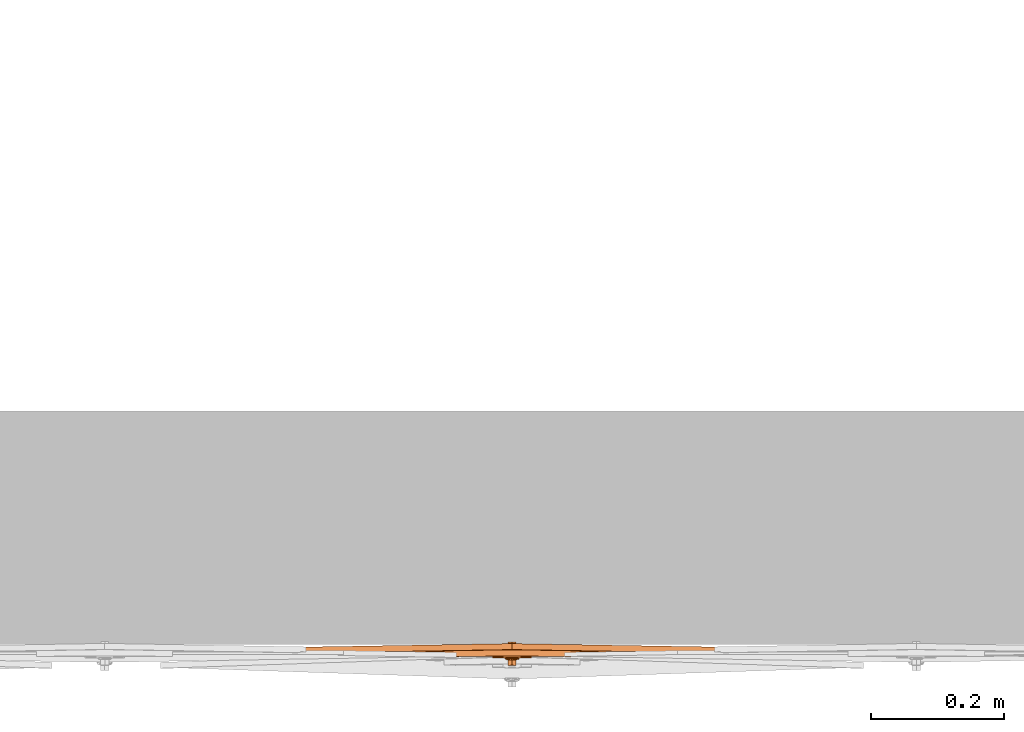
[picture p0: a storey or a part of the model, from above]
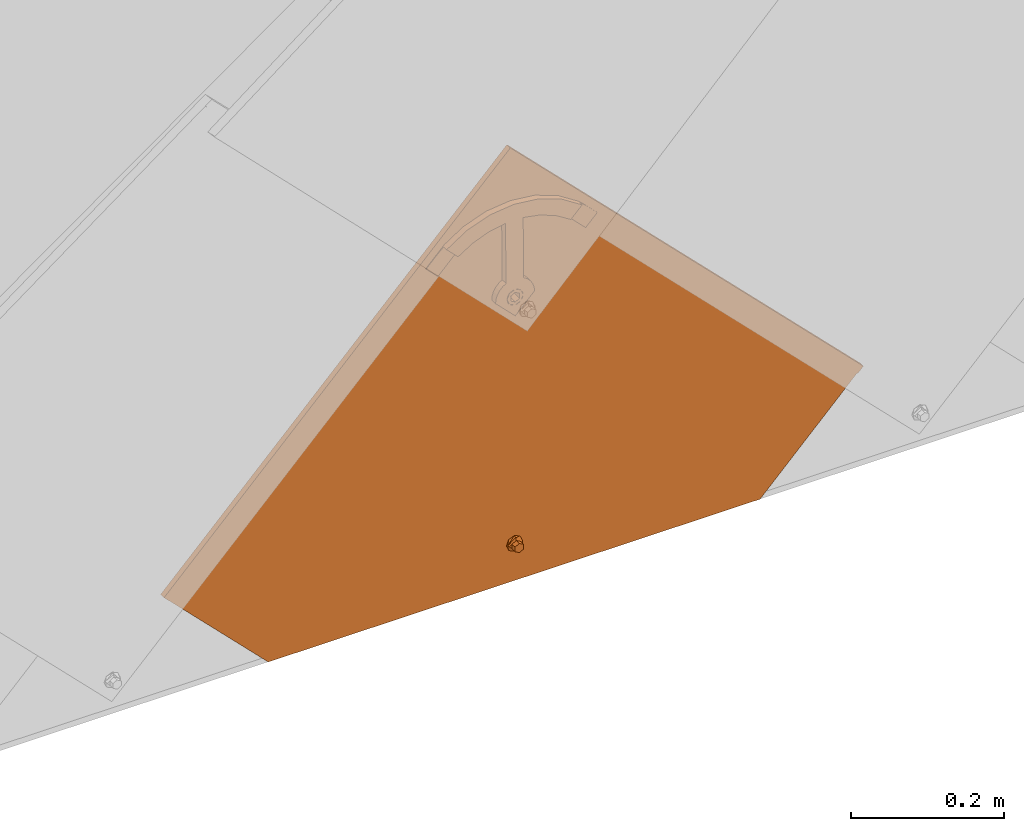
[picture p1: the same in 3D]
Properties of the parts of a building model (IFC2X3)

# File
Description: ViewDefinition [CoordinationView_V2.0]
File name: 0001
Time: 2023-04-02T02:29:55
Written by: The EXPRESS Data Manager Version 5.02.0100.07 : 28 Aug 2013
Made in: 20190327_2315(x64) - Exporter 20.0.0.377 - Alternate UI 20.0.0.377
Comment: STEP Physical File produced by: The EXPRESS Data Manager Version 5.02.0100.07 : 28 Aug 2013 * Module: EDMstepFileFactory/EDMstandAlone * Creation date: Sun Apr 02 02:29:55 2023 * Host: E7270 * Database: C:\Users\GOODLU~1\AppData\Local\Temp\f6eb3f9f-7fa0-42ba-b934-946579097e53\dbb1e1d8-6f93-475a-80dd-ea82b20c156a\ifc * Database version: 5507 * Database creation date: Sun Apr 02 02:29:47 2023 * Schema: IFC2X3 * Model: DataRepository.ifc * Model creation date: Sun Apr 02 02:29:48 2023 * Header model: DataRepository.ifc_HeaderModel * Header model creation date: Sun Apr 02 02:29:48 2023 * EDMuser: sdai-user * EDMgroup: sdai-group * License ID and type: 5605 : Permanent license. Expiry date: * EDMstepFileFactory options: 020000

# IfcProject, 0001
LongName: Project Name; Phase: Project Status

# IfcSite, Default
RefLatitude: 42, 21, 30, 344238; RefLongitude: -71, -3, -35, -194702; RefElevation: 0 mm

# IfcBuilding
Pset_BuildingCommon - NumberOfStoreys: 2
Pset_ProductRequirements - Category: Project Information

# IfcBuildingStorey: Level:8mm Head (2)
Pset_ProductRequirements - Category: Levels
Name | LongName = Pset_AirSideSystemInformation, Name = Pset_ProductRequirements, Name | Elevation (mm)
Level 1 | Level 1 | 0
Level 2 | Level 2 | 2687.5

# IfcBuildingElementProxy: Corner Bottom Big Left - Black, Roofing_Panels_SunStyle_Tile_Corner-Bottom-Big-Left:Corner Bottom Big Left - Black:395826
In: Level 1
Type - Classification: B3010150 Roofing - Shingle & Tile (Uniformat); Material: Rubber - Sunstyle - Black, Glass - Sunstyle - Tainted Black
Type - Pset_BuildingElementProxyCommon - Reference: Corner Bottom Big Left - Black
Type - Pset_ManufacturerTypeInformation - Manufacturer: SunStyle
Type - Pset_ProductRequirements - Category: Generic Models
Type - Pset_QuantityTakeOff - Reference: Corner Bottom Big Left - Black
Pset_BuildingElementProxyCommon - sets with these values: 2

# IfcBuildingElementProxy: Corner Bottom Big Right - Black (12)
In: Level 1
Type - Classification: B3010150 Roofing - Shingle & Tile (Uniformat); Material: Rubber - Sunstyle - Black, Glass - Sunstyle - Tainted Black
Type - Pset_BuildingElementProxyCommon - Reference: Corner Bottom Big Right - Black
Type - Pset_ManufacturerTypeInformation - Manufacturer: SunStyle
Type - Pset_ProductRequirements - Category: Generic Models
Type - Pset_QuantityTakeOff - Reference: Corner Bottom Big Right - Black
Pset_BuildingElementProxyCommon - sets with these values: 2
Name (Roofing_Panels_SunStyle_Tile_Corner-Bottom-Big-Right:Corner Bottom Big Right - Black:...)
369701
377953
378203
386429
395871
516759
525238
525277
525309
525338
525370
525403

# IfcBuildingElementProxy: Corner Bottom Big Right - Terracotta, Roofing_Panels_SunStyle_Tile_Corner-Bottom-Big-Right:Corner Bottom Big Right - Terracotta:399702
In: Level 1
Type - Classification: B3010150 Roofing - Shingle & Tile (Uniformat); Material: Rubber - Sunstyle - Black, Glass - Sunstyle - Tainted Terracotta
Type - Pset_BuildingElementProxyCommon - Reference: Corner Bottom Big Right - Terracotta
Type - Pset_ManufacturerTypeInformation - Manufacturer: SunStyle
Type - Pset_ProductRequirements - Category: Generic Models
Type - Pset_QuantityTakeOff - Reference: Corner Bottom Big Right - Terracotta
Pset_BuildingElementProxyCommon - sets with these values: 2

# IfcBuildingElementProxy: Corner Bottom Small Left - Black (4)
In: Level 1
Type - Classification: B3010150 Roofing - Shingle & Tile (Uniformat); Material: Rubber - Sunstyle - Black, Glass - Sunstyle - Tainted Black
Type - Pset_BuildingElementProxyCommon - Reference: Corner Bottom Small Left - Black
Type - Pset_ManufacturerTypeInformation - Manufacturer: SunStyle
Type - Pset_ProductRequirements - Category: Generic Models
Type - Pset_QuantityTakeOff - Reference: Corner Bottom Small Left - Black
Pset_BuildingElementProxyCommon - sets with these values: 2
Name (Roofing_Panels_SunStyle_Tile_Corner-Bottom-Small-Left:Corner Bottom Small Left - Black:...)
369142
380725
385739
395835

# IfcBuildingElementProxy: Corner Bottom Small Left - Terracotta, Roofing_Panels_SunStyle_Tile_Corner-Bottom-Small-Left:Corner Bottom Small Left - Terracotta:401538
In: Level 1
Type - Classification: B3010150 Roofing - Shingle & Tile (Uniformat); Material: Rubber - Sunstyle - Black, Glass - Sunstyle - Tainted Terracotta
Type - Pset_BuildingElementProxyCommon - Reference: Corner Bottom Small Left - Terracotta
Type - Pset_ManufacturerTypeInformation - Manufacturer: SunStyle
Type - Pset_ProductRequirements - Category: Generic Models
Type - Pset_QuantityTakeOff - Reference: Corner Bottom Small Left - Terracotta
Pset_BuildingElementProxyCommon - sets with these values: 2

# IfcBuildingElementProxy: Corner Bottom Small Right - Black, Roofing_Panels_SunStyle_Tile_Corner-Bottom-Small-Right:Corner Bottom Small Right - Black:395880
In: Level 1
Type - Classification: B3010150 Roofing - Shingle & Tile (Uniformat); Material: Rubber - Sunstyle - Black, Glass - Sunstyle - Tainted Black
Type - Pset_BuildingElementProxyCommon - Reference: Corner Bottom Small Right - Black
Type - Pset_ManufacturerTypeInformation - Manufacturer: SunStyle
Type - Pset_ProductRequirements - Category: Generic Models
Type - Pset_QuantityTakeOff - Reference: Corner Bottom Small Right - Black
Pset_BuildingElementProxyCommon - sets with these values: 2

# IfcBuildingElementProxy: Corner Top Big Left - Black (3)
In: Level 1
Type - Classification: B3010150 Roofing - Shingle & Tile (Uniformat); Material: Rubber - Sunstyle - Black, Glass - Sunstyle - Tainted Black
Type - Pset_BuildingElementProxyCommon - Reference: Corner Top Big Left - Black
Type - Pset_ManufacturerTypeInformation - Manufacturer: SunStyle
Type - Pset_ProductRequirements - Category: Generic Models
Type - Pset_QuantityTakeOff - Reference: Corner Top Big Left - Black
Pset_BuildingElementProxyCommon - sets with these values: 2
Name (Roofing_Panels_SunStyle_Tile_Corner-Top-Big-Left:Corner Top Big Left - Black:...)
366997
386258
395853

# IfcBuildingElementProxy: Corner Top Big Left - Terracotta, Roofing_Panels_SunStyle_Tile_Corner-Top-Big-Left:Corner Top Big Left - Terracotta:400910
In: Level 1
Type - Classification: B3010150 Roofing - Shingle & Tile (Uniformat); Material: Rubber - Sunstyle - Black, Glass - Sunstyle - Tainted Terracotta
Type - Pset_BuildingElementProxyCommon - Reference: Corner Top Big Left - Terracotta
Type - Pset_ManufacturerTypeInformation - Manufacturer: SunStyle
Type - Pset_ProductRequirements - Category: Generic Models
Type - Pset_QuantityTakeOff - Reference: Corner Top Big Left - Terracotta
Pset_BuildingElementProxyCommon - sets with these values: 2

# IfcBuildingElementProxy: Corner Top Big Right - Black, Roofing_Panels_SunStyle_Tile_Corner-Top-Big-Right:Corner Top Big Right - Black:395898
In: Level 1
Type - Classification: B3010150 Roofing - Shingle & Tile (Uniformat); Material: Rubber - Sunstyle - Black, Glass - Sunstyle - Tainted Black
Type - Pset_BuildingElementProxyCommon - Reference: Corner Top Big Right - Black
Type - Pset_ManufacturerTypeInformation - Manufacturer: SunStyle
Type - Pset_ProductRequirements - Category: Generic Models
Type - Pset_QuantityTakeOff - Reference: Corner Top Big Right - Black
Pset_BuildingElementProxyCommon - sets with these values: 2

# IfcBuildingElementProxy: Corner Top Small Left - Black, Roofing_Panels_SunStyle_Tile_Corner-Top-Small-Left:Corner Top Small Left - Black:395862
In: Level 1
Type - Classification: B3010150 Roofing - Shingle & Tile (Uniformat); Material: Rubber - Sunstyle - Black, Glass - Sunstyle - Tainted Black
Type - Pset_BuildingElementProxyCommon - Reference: Corner Top Small Left - Black
Type - Pset_ManufacturerTypeInformation - Manufacturer: SunStyle
Type - Pset_ProductRequirements - Category: Generic Models
Type - Pset_QuantityTakeOff - Reference: Corner Top Small Left - Black
Pset_BuildingElementProxyCommon - sets with these values: 2

# IfcBuildingElementProxy: Corner Top Small Right - Black (3)
In: Level 1
Type - Classification: B3010150 Roofing - Shingle & Tile (Uniformat); Material: Rubber - Sunstyle - Black, Glass - Sunstyle - Tainted Black
Type - Pset_BuildingElementProxyCommon - Reference: Corner Top Small Right - Black
Type - Pset_ManufacturerTypeInformation - Manufacturer: SunStyle
Type - Pset_ProductRequirements - Category: Generic Models
Type - Pset_QuantityTakeOff - Reference: Corner Top Small Right - Black
Pset_BuildingElementProxyCommon - sets with these values: 2
Name (Roofing_Panels_SunStyle_Tile_Corner-Top-Small-Right:Corner Top Small Right - Black:...)
379696
386932
395907

# IfcBuildingElementProxy: Corner Top Small Right - Terracotta, Roofing_Panels_SunStyle_Tile_Corner-Top-Small-Right:Corner Top Small Right - Terracotta:400462
In: Level 1
Type - Classification: B3010150 Roofing - Shingle & Tile (Uniformat); Material: Rubber - Sunstyle - Black, Glass - Sunstyle - Tainted Terracotta
Type - Pset_BuildingElementProxyCommon - Reference: Corner Top Small Right - Terracotta
Type - Pset_ManufacturerTypeInformation - Manufacturer: SunStyle
Type - Pset_ProductRequirements - Category: Generic Models
Type - Pset_QuantityTakeOff - Reference: Corner Top Small Right - Terracotta
Pset_BuildingElementProxyCommon - sets with these values: 2

# IfcBuildingElementProxy: Non PV Shingle - Black (9)
In: Level 1
Type - Classification: B3010150 Roofing - Shingle & Tile (Uniformat); Material: Rubber - Sunstyle - Black, Glass - Sunstyle - Tainted Black
Type - Pset_BuildingElementProxyCommon - Reference: Non PV Shingle - Black
Type - Pset_ManufacturerTypeInformation - Manufacturer: SunStyle
Type - Pset_ProductRequirements - Category: Generic Models
Type - Pset_QuantityTakeOff - Reference: Non PV Shingle - Black
Pset_BuildingElementProxyCommon - sets with these values: 2
Name (Roofing_Panels_SunStyle_Tile_Non-PV-Shingle:Non PV Shingle - Black:...)
384084
384306
384333
384420
384541
384610
384709
384800
395796

# IfcBuildingElementProxy: Non PV Shingle - Silver, Roofing_Panels_SunStyle_Tile_Non-PV-Shingle:Non PV Shingle - Silver:403169
In: Level 2
Type - Classification: B3010150 Roofing - Shingle & Tile (Uniformat); Material: Rubber - Sunstyle - Black, Glass - Sunstyle - Tainted Silver
Type - Pset_BuildingElementProxyCommon - Reference: Non PV Shingle - Silver
Type - Pset_ManufacturerTypeInformation - Manufacturer: SunStyle
Type - Pset_ProductRequirements - Category: Generic Models
Type - Pset_QuantityTakeOff - Reference: Non PV Shingle - Silver
Pset_BuildingElementProxyCommon - sets with these values: 2

# IfcBuildingElementProxy: Non PV Shingle - Terracotta (4)
In: Level 1
Type - Classification: B3010150 Roofing - Shingle & Tile (Uniformat); Material: Rubber - Sunstyle - Black, Glass - Sunstyle - Tainted Terracotta
Type - Pset_BuildingElementProxyCommon - Reference: Non PV Shingle - Terracotta
Type - Pset_ManufacturerTypeInformation - Manufacturer: SunStyle
Type - Pset_ProductRequirements - Category: Generic Models
Type - Pset_QuantityTakeOff - Reference: Non PV Shingle - Terracotta
Pset_BuildingElementProxyCommon - sets with these values: 2
Name (Roofing_Panels_SunStyle_Tile_Non-PV-Shingle:Non PV Shingle - Terracotta:...)
398031
398120
498498
498499

# IfcBuildingElementProxy: Shingle Bottom - Black (11)
In: Level 1
Type - Classification: B3010150 Roofing - Shingle & Tile (Uniformat); Material: Rubber - Sunstyle - Black, Glass - Sunstyle - Tainted Black
Type - Pset_BuildingElementProxyCommon - Reference: Shingle Bottom - Black
Type - Pset_ManufacturerTypeInformation - Manufacturer: SunStyle
Type - Pset_ProductRequirements - Category: Generic Models
Type - Pset_QuantityTakeOff - Reference: Shingle Bottom - Black
Pset_BuildingElementProxyCommon - sets with these values: 2
Name (Roofing_Panels_SunStyle_Tile_Shingle-Bottom:Shingle Bottom - Black:...)
368326
385063
385148
395808
495417
495439
495456
495473
495487
495504
495520

# IfcBuildingElementProxy: Shingle Bottom - Terracotta (2)
In: Level 1
Type - Classification: B3010150 Roofing - Shingle & Tile (Uniformat); Material: Rubber - Sunstyle - Black, Glass - Sunstyle - Tainted Terracotta
Type - Pset_BuildingElementProxyCommon - Reference: Shingle Bottom - Terracotta
Type - Pset_ManufacturerTypeInformation - Manufacturer: SunStyle
Type - Pset_ProductRequirements - Category: Generic Models
Type - Pset_QuantityTakeOff - Reference: Shingle Bottom - Terracotta
Pset_BuildingElementProxyCommon - sets with these values: 2
Name (Roofing_Panels_SunStyle_Tile_Shingle-Bottom:Shingle Bottom - Terracotta:...)
398686
498471

# IfcBuildingElementProxy: Shingle Bottom Small - Black (19)
In: Level 1
Type - Classification: B3010150 Roofing - Shingle & Tile (Uniformat); Material: Rubber - Sunstyle - Black, Glass - Sunstyle - Tainted Black
Type - Pset_BuildingElementProxyCommon - Reference: Shingle Bottom Small - Black
Type - Pset_ManufacturerTypeInformation - Manufacturer: SunStyle
Type - Pset_ProductRequirements - Category: Generic Models
Type - Pset_QuantityTakeOff - Reference: Shingle Bottom Small - Black
Pset_BuildingElementProxyCommon - sets with these values: 2
Name (Roofing_Panels_SunStyle_Tile_Shingle-Bottom-Small:Shingle Bottom Small - Black:...)
367801
380429
387918
388031
395817
495637
495653
495669
495683
495697
495761
495787
524312
525246
525278
525310
525339
525371
525404

# IfcBuildingElementProxy: Shingle Bottom Small - Terracotta (2)
In: Level 1
Type - Classification: B3010150 Roofing - Shingle & Tile (Uniformat); Material: Rubber - Sunstyle - Black, Glass - Sunstyle - Tainted Terracotta
Type - Pset_BuildingElementProxyCommon - Reference: Shingle Bottom Small - Terracotta
Type - Pset_ManufacturerTypeInformation - Manufacturer: SunStyle
Type - Pset_ProductRequirements - Category: Generic Models
Type - Pset_QuantityTakeOff - Reference: Shingle Bottom Small - Terracotta
Pset_BuildingElementProxyCommon - sets with these values: 2
Name (Roofing_Panels_SunStyle_Tile_Shingle-Bottom-Small:Shingle Bottom Small - Terracotta:...)
401826
498501

# IfcBuildingElementProxy: Shingle Customisable - Black, Roofing_Panels_SunStyle_Tile_Shingle-Customisable:Shingle Customisable - Black:404367
In: Level 1
Type - Classification: B3010150 Roofing - Shingle & Tile (Uniformat); Material: Rubber - Sunstyle - Black, Glass - Sunstyle - Tainted Black
Type - Pset_BuildingElementProxyCommon - Reference: Shingle Customisable - Black
Type - Pset_ManufacturerTypeInformation - Manufacturer: SunStyle
Type - Pset_ProductRequirements - Category: Generic Models
Type - Pset_QuantityTakeOff - Reference: Shingle Customisable - Black
Pset_BuildingElementProxyCommon - sets with these values: 2

# IfcBuildingElementProxy: Shingle Left - Black (11)
In: Level 1
Type - Classification: B3010150 Roofing - Shingle & Tile (Uniformat); Material: Rubber - Sunstyle - Black, Glass - Sunstyle - Tainted Black
Type - Pset_BuildingElementProxyCommon - Reference: Shingle Left - Black
Type - Pset_ManufacturerTypeInformation - Manufacturer: SunStyle
Type - Pset_ProductRequirements - Category: Generic Models
Type - Pset_QuantityTakeOff - Reference: Shingle Left - Black
Pset_BuildingElementProxyCommon - sets with these values: 2
Name (Roofing_Panels_SunStyle_Tile_Shingle-Left:Shingle Left - Black:...)
363329
363472
363536
377368
377509
377580
377661
385898
385981
395844
522810

# IfcBuildingElementProxy: Shingle Left - Terracotta (2)
In: Level 1
Type - Classification: B3010150 Roofing - Shingle & Tile (Uniformat); Material: Rubber - Sunstyle - Black, Glass - Sunstyle - Tainted Terracotta
Type - Pset_BuildingElementProxyCommon - Reference: Shingle Left - Terracotta
Type - Pset_ManufacturerTypeInformation - Manufacturer: SunStyle
Type - Pset_ProductRequirements - Category: Generic Models
Type - Pset_QuantityTakeOff - Reference: Shingle Left - Terracotta
Pset_BuildingElementProxyCommon - sets with these values: 2
Name (Roofing_Panels_SunStyle_Tile_Shingle-Left:Shingle Left - Terracotta:...)
401137
401240

# IfcBuildingElementProxy: Shingle Right - Black (11)
In: Level 1
Type - Classification: B3010150 Roofing - Shingle & Tile (Uniformat); Material: Rubber - Sunstyle - Black, Glass - Sunstyle - Tainted Black
Type - Pset_BuildingElementProxyCommon - Reference: Shingle Right - Black
Type - Pset_ManufacturerTypeInformation - Manufacturer: SunStyle
Type - Pset_ProductRequirements - Category: Generic Models
Type - Pset_QuantityTakeOff - Reference: Shingle Right - Black
Pset_BuildingElementProxyCommon - sets with these values: 2
Name (Roofing_Panels_SunStyle_Tile_Shingle-Right:Shingle Right - Black:...)
364398
364494
364559
364595
376955
377074
377135
377220
386670
386833
395889

# IfcBuildingElementProxy: Shingle Right - Terracotta (2)
In: Level 1
Type - Classification: B3010150 Roofing - Shingle & Tile (Uniformat); Material: Rubber - Sunstyle - Black, Glass - Sunstyle - Tainted Terracotta
Type - Pset_BuildingElementProxyCommon - Reference: Shingle Right - Terracotta
Type - Pset_ManufacturerTypeInformation - Manufacturer: SunStyle
Type - Pset_ProductRequirements - Category: Generic Models
Type - Pset_QuantityTakeOff - Reference: Shingle Right - Terracotta
Pset_BuildingElementProxyCommon - sets with these values: 2
Name (Roofing_Panels_SunStyle_Tile_Shingle-Right:Shingle Right - Terracotta:...)
399878
400171

# IfcBuildingElementProxy: Shingle Sunstyle - Black (130)
In: Level 1
Type - Classification: B3010150 Roofing - Shingle & Tile (Uniformat); Material: Rubber - Sunstyle - Black, Glass - Sunstyle - Tainted Black, Steel - Sunstyle - Clear Coated Steel
Type - Pset_BuildingElementProxyCommon - Reference: Shingle Sunstyle - Black
Type - Pset_ManufacturerTypeInformation - Manufacturer: SunStyle
Type - Pset_ProductRequirements - Category: Generic Models
Type - Pset_QuantityTakeOff - Reference: Shingle Sunstyle - Black
Pset_BuildingElementProxyCommon - sets with these values: 2
Name (Roofing_Solar-Panels_SunStyle_Shingle-Sunstyle:Shingle Sunstyle - Black:...)
354499
355628
355733
355931
355994
356179
368948
376161
376228
381722 | Group: <unnamed>
395934
487199
488894
489124
495414
495438
495455
495472
495486
495503
495519
495633
495638
495652
495654
495668
495670
495682
495684
495698
495762
495786
495788
508846
508851
508880
508882
509027
509031
509033
509039
517179
517181
517182
517183
517184
517186
517205
517207
517208
517209
517210
517212
517229
517231
517272
517273
517288
517289
517300
517301
517800
517880
518140
518201
518335
518360
518440
518466
518521
524886
524887
524889
525041
525061
525062
525064
525066
525247
525248
525249
525250
525251
525252
525254
525255
525279
525280
525281
525282
525283
525284
525286
525287
525311
525312
525313
525314
525315
525316
525318
525319
525340
525341
525342
525343
525344
525345
525347
525348
525372
525373
525374
525375
525376
525377
525379
525380
525405
525406
525407
525408
525409
525410
525412
525413
525438
525439
525440
525441

# IfcBuildingElementProxy: Shingle Sunstyle - Silver, Roofing_Solar-Panels_SunStyle_Shingle-Sunstyle:Shingle Sunstyle - Silver:381744
In: Level 1
Type - Classification: B3010150 Roofing - Shingle & Tile (Uniformat); Material: Rubber - Sunstyle - Black, Glass - Sunstyle - Tainted Black, Steel - Sunstyle - Clear Coated Steel
Type - Pset_BuildingElementProxyCommon - Reference: Shingle Sunstyle - Silver
Type - Pset_ManufacturerTypeInformation - Manufacturer: SunStyle
Type - Pset_ProductRequirements - Category: Generic Models
Type - Pset_QuantityTakeOff - Reference: Shingle Sunstyle - Silver
Pset_BuildingElementProxyCommon - sets with these values: 2

# IfcBuildingElementProxy: Shingle Top - Black (19)
In: Level 1
Type - Classification: B3010150 Roofing - Shingle & Tile (Uniformat); Material: Rubber - Sunstyle - Black, Glass - Sunstyle - Tainted Black
Type - Pset_BuildingElementProxyCommon - Reference: Shingle Top - Black
Type - Pset_ManufacturerTypeInformation - Manufacturer: SunStyle
Type - Pset_ProductRequirements - Category: Generic Models
Type - Pset_QuantityTakeOff - Reference: Shingle Top - Black
Pset_BuildingElementProxyCommon - sets with these values: 2
Name (Roofing_Panels_SunStyle_Tile_Shingle-Top:Shingle Top - Black:...)
364669
376833
387079
387226
395916
508849
509036
517180
517185
517206
517211
517230
525063
525253
525285
525317
525346
525378
525411

# IfcBuildingElementProxy: Shingle Top - Terracotta (2)
In: Level 1
Type - Classification: B3010150 Roofing - Shingle & Tile (Uniformat); Material: Rubber - Sunstyle - Black, Glass - Sunstyle - Tainted Terracotta
Type - Pset_BuildingElementProxyCommon - Reference: Shingle Top - Terracotta
Type - Pset_ManufacturerTypeInformation - Manufacturer: SunStyle
Type - Pset_ProductRequirements - Category: Generic Models
Type - Pset_QuantityTakeOff - Reference: Shingle Top - Terracotta
Pset_BuildingElementProxyCommon - sets with these values: 2
Name (Roofing_Panels_SunStyle_Tile_Shingle-Top:Shingle Top - Terracotta:...)
400702
498500

# IfcBuildingElementProxy: Shingle Top Small - Black (3)
In: Level 1
Type - Classification: B3010150 Roofing - Shingle & Tile (Uniformat); Material: Rubber - Sunstyle - Black, Glass - Sunstyle - Tainted Black
Type - Pset_BuildingElementProxyCommon - Reference: Shingle Top Small - Black
Type - Pset_ManufacturerTypeInformation - Manufacturer: SunStyle
Type - Pset_ProductRequirements - Category: Generic Models
Type - Pset_QuantityTakeOff - Reference: Shingle Top Small - Black
Pset_BuildingElementProxyCommon - sets with these values: 2
Name (Roofing_Panels_SunStyle_Tile_Shingle-Top-Small:Shingle Top Small - Black:...)
387334
387369
395925

# IfcBuildingElementProxy: Shingle Top Small - Terracotta (2)
In: Level 1
Type - Classification: B3010150 Roofing - Shingle & Tile (Uniformat); Material: Rubber - Sunstyle - Black, Glass - Sunstyle - Tainted Terracotta
Type - Pset_BuildingElementProxyCommon - Reference: Shingle Top Small - Terracotta
Type - Pset_ManufacturerTypeInformation - Manufacturer: SunStyle
Type - Pset_ProductRequirements - Category: Generic Models
Type - Pset_QuantityTakeOff - Reference: Shingle Top Small - Terracotta
Pset_BuildingElementProxyCommon - sets with these values: 2
Name (Roofing_Panels_SunStyle_Tile_Shingle-Top-Small:Shingle Top Small - Terracotta:...)
397241
498467

# IfcBuildingElementProxy: Shingle-Sunstyle - Terracotta (5)
In: Level 1
Type - Classification: B3010150 Roofing - Shingle & Tile (Uniformat); Material: Rubber - Sunstyle - Black, Glass - Sunstyle - Tainted Black, Steel - Sunstyle - Clear Coated Steel
Type - Pset_BuildingElementProxyCommon - Reference: Shingle-Sunstyle - Terracotta
Type - Pset_ManufacturerTypeInformation - Manufacturer: SunStyle
Type - Pset_ProductRequirements - Category: Generic Models
Type - Pset_QuantityTakeOff - Reference: Shingle-Sunstyle - Terracotta
Pset_BuildingElementProxyCommon - sets with these values: 2
Name (Roofing_Solar-Panels_SunStyle_Shingle-Sunstyle:Shingle-Sunstyle - Terracotta:...)
381754
397362
397667
498469
498470

# IfcBuildingElementProxy: Structural Framing 1 (14)
In: Level 1
Type - Material: Wood - Generic - Wood For Showcase
Type - Pset_BuildingElementProxyCommon - Reference: Structural Framing 1
Type - Pset_ProductRequirements - Category: Structural Framing
Type - Pset_QuantityTakeOff - Reference: Structural Framing 1
Pset_BuildingElementProxyCommon - sets with these values: 2
Name
Structural Framing 1:Structural Framing 1:323502
Structural Framing 2:Structural Framing 1:323542
Structural Framing 3:Structural Framing 1:323562
Structural Framing 4:Structural Framing 1:323582
Structural Framing 5:Structural Framing 1:323602
Structural Framing 6:Structural Framing 1:323622
Structural Framing 7:Structural Framing 1:323642
Structural Framing 8:Structural Framing 1:323662
Structural Framing 9:Structural Framing 1:323682
Structural Framing 10:Structural Framing 1:323702
Structural Framing 11:Structural Framing 1:323722
Structural Framing 12:Structural Framing 1:323742
Structural Framing 13:Structural Framing 1:323762
Structural Framing 14:Structural Framing 1:323782

# IfcBuildingElementProxy: Structural Framing 15 (280)
In: Level 1
Type - Material: Wood - Generic - Wood For Showcase
Type - Pset_BuildingElementProxyCommon - Reference: Structural Framing 15
Type - Pset_ProductRequirements - Category: Structural Framing
Type - Pset_QuantityTakeOff - Reference: Structural Framing 15
Pset_BuildingElementProxyCommon - sets with these values: 2
Name
Structural Framing 155:Structural Framing 15:327129
Structural Framing 156:Structural Framing 15:327141
Structural Framing 157:Structural Framing 15:327153
Structural Framing 158:Structural Framing 15:327165
Structural Framing 159:Structural Framing 15:327177
Structural Framing 160:Structural Framing 15:327189
Structural Framing 161:Structural Framing 15:327201
Structural Framing 162:Structural Framing 15:327213
Structural Framing 163:Structural Framing 15:327225
Structural Framing 164:Structural Framing 15:327237
Structural Framing 165:Structural Framing 15:327249
Structural Framing 166:Structural Framing 15:327261
Structural Framing 167:Structural Framing 15:327273
Structural Framing 168:Structural Framing 15:327285
Structural Framing 169:Structural Framing 15:327297
Structural Framing 170:Structural Framing 15:327309
Structural Framing 171:Structural Framing 15:327321
Structural Framing 172:Structural Framing 15:327333
Structural Framing 173:Structural Framing 15:327345
Structural Framing 174:Structural Framing 15:327357
Structural Framing 175:Structural Framing 15:327369
Structural Framing 176:Structural Framing 15:327381
Structural Framing 177:Structural Framing 15:327393
Structural Framing 178:Structural Framing 15:327405
Structural Framing 179:Structural Framing 15:327417
Structural Framing 180:Structural Framing 15:327429
Structural Framing 181:Structural Framing 15:327441
Structural Framing 182:Structural Framing 15:327453
Structural Framing 183:Structural Framing 15:327465
Structural Framing 184:Structural Framing 15:327477
Structural Framing 185:Structural Framing 15:327489
Structural Framing 186:Structural Framing 15:327501
Structural Framing 187:Structural Framing 15:327513
Structural Framing 188:Structural Framing 15:327525
Structural Framing 189:Structural Framing 15:327537
Structural Framing 190:Structural Framing 15:327549
Structural Framing 191:Structural Framing 15:327561
Structural Framing 192:Structural Framing 15:327573
Structural Framing 193:Structural Framing 15:327585
Structural Framing 194:Structural Framing 15:327597
Structural Framing 195:Structural Framing 15:327609
Structural Framing 196:Structural Framing 15:327621
Structural Framing 197:Structural Framing 15:327633
Structural Framing 198:Structural Framing 15:327645
Structural Framing 199:Structural Framing 15:327657
Structural Framing 200:Structural Framing 15:327669
Structural Framing 201:Structural Framing 15:327681
Structural Framing 202:Structural Framing 15:327693
Structural Framing 203:Structural Framing 15:327705
Structural Framing 204:Structural Framing 15:327717
Structural Framing 205:Structural Framing 15:327729
Structural Framing 206:Structural Framing 15:327741
Structural Framing 207:Structural Framing 15:327753
Structural Framing 208:Structural Framing 15:327765
Structural Framing 209:Structural Framing 15:327777
Structural Framing 210:Structural Framing 15:327789
Structural Framing 211:Structural Framing 15:327801
Structural Framing 212:Structural Framing 15:327813
Structural Framing 213:Structural Framing 15:327825
Structural Framing 214:Structural Framing 15:327837
Structural Framing 215:Structural Framing 15:327849
Structural Framing 216:Structural Framing 15:327861
Structural Framing 217:Structural Framing 15:327873
Structural Framing 218:Structural Framing 15:327885
Structural Framing 219:Structural Framing 15:327897
Structural Framing 220:Structural Framing 15:327909
Structural Framing 221:Structural Framing 15:327921
Structural Framing 222:Structural Framing 15:327933
Structural Framing 223:Structural Framing 15:327945
Structural Framing 224:Structural Framing 15:327957
Structural Framing 225:Structural Framing 15:327969
Structural Framing 226:Structural Framing 15:327981
Structural Framing 227:Structural Framing 15:327993
Structural Framing 228:Structural Framing 15:328005
Structural Framing 229:Structural Framing 15:328017
Structural Framing 230:Structural Framing 15:328029
Structural Framing 231:Structural Framing 15:328041
Structural Framing 232:Structural Framing 15:328053
Structural Framing 233:Structural Framing 15:328065
Structural Framing 234:Structural Framing 15:328077
Structural Framing 235:Structural Framing 15:328089
Structural Framing 236:Structural Framing 15:328101
Structural Framing 237:Structural Framing 15:328113
Structural Framing 238:Structural Framing 15:328125
Structural Framing 239:Structural Framing 15:328137
Structural Framing 240:Structural Framing 15:328149
Structural Framing 241:Structural Framing 15:328161
Structural Framing 242:Structural Framing 15:328173
Structural Framing 243:Structural Framing 15:328185
Structural Framing 244:Structural Framing 15:328197
Structural Framing 245:Structural Framing 15:328209
Structural Framing 246:Structural Framing 15:328221
Structural Framing 247:Structural Framing 15:328233
Structural Framing 248:Structural Framing 15:328245
Structural Framing 249:Structural Framing 15:328257
Structural Framing 250:Structural Framing 15:328269
Structural Framing 251:Structural Framing 15:328281
Structural Framing 252:Structural Framing 15:328293
Structural Framing 253:Structural Framing 15:328305
Structural Framing 254:Structural Framing 15:328317
Structural Framing 255:Structural Framing 15:328329
Structural Framing 256:Structural Framing 15:328341
Structural Framing 257:Structural Framing 15:328353
Structural Framing 258:Structural Framing 15:328365
Structural Framing 259:Structural Framing 15:328377
Structural Framing 260:Structural Framing 15:328389
Structural Framing 261:Structural Framing 15:328401
Structural Framing 262:Structural Framing 15:328413
Structural Framing 263:Structural Framing 15:328425
Structural Framing 264:Structural Framing 15:328437
Structural Framing 265:Structural Framing 15:328449
Structural Framing 266:Structural Framing 15:328461
Structural Framing 267:Structural Framing 15:328473
Structural Framing 268:Structural Framing 15:328485
Structural Framing 269:Structural Framing 15:328497
Structural Framing 270:Structural Framing 15:328509
Structural Framing 271:Structural Framing 15:328521
Structural Framing 272:Structural Framing 15:328533
Structural Framing 273:Structural Framing 15:328545
Structural Framing 274:Structural Framing 15:328557
Structural Framing 275:Structural Framing 15:328569
Structural Framing 276:Structural Framing 15:328581
Structural Framing 277:Structural Framing 15:328593
Structural Framing 278:Structural Framing 15:328605
Structural Framing 279:Structural Framing 15:328617
Structural Framing 280:Structural Framing 15:328629
Structural Framing 281:Structural Framing 15:328641
Structural Framing 282:Structural Framing 15:328653
Structural Framing 283:Structural Framing 15:328665
Structural Framing 284:Structural Framing 15:328677
Structural Framing 285:Structural Framing 15:328689
Structural Framing 286:Structural Framing 15:328701
Structural Framing 287:Structural Framing 15:328713
Structural Framing 288:Structural Framing 15:328725
Structural Framing 289:Structural Framing 15:328737
Structural Framing 293:Structural Framing 15:328785
Structural Framing 290:Structural Framing 15:329894
Structural Framing 291:Structural Framing 15:329914
Structural Framing 292:Structural Framing 15:329932
Structural Framing 294:Structural Framing 15:330024
Structural Framing 15:Structural Framing 15:330272
Structural Framing 16:Structural Framing 15:330284
Structural Framing 17:Structural Framing 15:330296
Structural Framing 18:Structural Framing 15:330308
Structural Framing 19:Structural Framing 15:330320
Structural Framing 20:Structural Framing 15:330332
Structural Framing 21:Structural Framing 15:330344
Structural Framing 22:Structural Framing 15:330356
Structural Framing 23:Structural Framing 15:330368
Structural Framing 24:Structural Framing 15:330380
Structural Framing 25:Structural Framing 15:330392
Structural Framing 26:Structural Framing 15:330404
Structural Framing 27:Structural Framing 15:330416
Structural Framing 28:Structural Framing 15:330428
Structural Framing 29:Structural Framing 15:330440
Structural Framing 30:Structural Framing 15:330452
Structural Framing 31:Structural Framing 15:330464
Structural Framing 32:Structural Framing 15:330476
Structural Framing 33:Structural Framing 15:330488
Structural Framing 34:Structural Framing 15:330500
Structural Framing 35:Structural Framing 15:330512
Structural Framing 36:Structural Framing 15:330524
Structural Framing 37:Structural Framing 15:330536
Structural Framing 38:Structural Framing 15:330548
Structural Framing 39:Structural Framing 15:330560
Structural Framing 40:Structural Framing 15:330572
Structural Framing 41:Structural Framing 15:330584
Structural Framing 42:Structural Framing 15:330596
Structural Framing 43:Structural Framing 15:330608
Structural Framing 44:Structural Framing 15:330620
Structural Framing 45:Structural Framing 15:330632
Structural Framing 46:Structural Framing 15:330644
Structural Framing 47:Structural Framing 15:330656
Structural Framing 48:Structural Framing 15:330668
Structural Framing 49:Structural Framing 15:330680
Structural Framing 50:Structural Framing 15:330692
Structural Framing 51:Structural Framing 15:330704
Structural Framing 52:Structural Framing 15:330716
Structural Framing 53:Structural Framing 15:330728
Structural Framing 54:Structural Framing 15:330740
Structural Framing 55:Structural Framing 15:330752
Structural Framing 56:Structural Framing 15:330764
Structural Framing 57:Structural Framing 15:330776
Structural Framing 58:Structural Framing 15:330788
Structural Framing 59:Structural Framing 15:330800
Structural Framing 60:Structural Framing 15:330812
Structural Framing 61:Structural Framing 15:330824
Structural Framing 62:Structural Framing 15:330836
Structural Framing 63:Structural Framing 15:330848
Structural Framing 64:Structural Framing 15:330860
Structural Framing 65:Structural Framing 15:330872
Structural Framing 66:Structural Framing 15:330884
Structural Framing 67:Structural Framing 15:330896
Structural Framing 68:Structural Framing 15:330908
Structural Framing 69:Structural Framing 15:330920
Structural Framing 70:Structural Framing 15:330932
Structural Framing 71:Structural Framing 15:330944
Structural Framing 72:Structural Framing 15:330956
Structural Framing 73:Structural Framing 15:330968
Structural Framing 74:Structural Framing 15:330980
Structural Framing 75:Structural Framing 15:330992
Structural Framing 76:Structural Framing 15:331004
Structural Framing 77:Structural Framing 15:331016
Structural Framing 78:Structural Framing 15:331028
Structural Framing 79:Structural Framing 15:331040
Structural Framing 80:Structural Framing 15:331052
Structural Framing 81:Structural Framing 15:331064
Structural Framing 82:Structural Framing 15:331076
Structural Framing 83:Structural Framing 15:331088
Structural Framing 84:Structural Framing 15:331100
Structural Framing 85:Structural Framing 15:331112
Structural Framing 86:Structural Framing 15:331124
Structural Framing 87:Structural Framing 15:331136
Structural Framing 88:Structural Framing 15:331148
Structural Framing 89:Structural Framing 15:331160
Structural Framing 90:Structural Framing 15:331172
Structural Framing 91:Structural Framing 15:331184
Structural Framing 92:Structural Framing 15:331196
Structural Framing 93:Structural Framing 15:331208
Structural Framing 94:Structural Framing 15:331220
Structural Framing 95:Structural Framing 15:331232
Structural Framing 96:Structural Framing 15:331244
Structural Framing 97:Structural Framing 15:331256
Structural Framing 98:Structural Framing 15:331268
Structural Framing 99:Structural Framing 15:331280
Structural Framing 100:Structural Framing 15:331292
Structural Framing 101:Structural Framing 15:331304
Structural Framing 102:Structural Framing 15:331316
Structural Framing 103:Structural Framing 15:331328
Structural Framing 104:Structural Framing 15:331340
Structural Framing 105:Structural Framing 15:331352
Structural Framing 106:Structural Framing 15:331364
Structural Framing 107:Structural Framing 15:331376
Structural Framing 108:Structural Framing 15:331388
Structural Framing 109:Structural Framing 15:331400
Structural Framing 110:Structural Framing 15:331412
Structural Framing 111:Structural Framing 15:331424
Structural Framing 112:Structural Framing 15:331436
Structural Framing 113:Structural Framing 15:331448
Structural Framing 114:Structural Framing 15:331460
Structural Framing 115:Structural Framing 15:331472
Structural Framing 116:Structural Framing 15:331484
Structural Framing 117:Structural Framing 15:331496
Structural Framing 118:Structural Framing 15:331508
Structural Framing 119:Structural Framing 15:331520
Structural Framing 120:Structural Framing 15:331532
Structural Framing 121:Structural Framing 15:331544
Structural Framing 122:Structural Framing 15:331556
Structural Framing 123:Structural Framing 15:331568
Structural Framing 124:Structural Framing 15:331580
Structural Framing 125:Structural Framing 15:331592
Structural Framing 126:Structural Framing 15:331604
Structural Framing 127:Structural Framing 15:331616
Structural Framing 128:Structural Framing 15:331628
Structural Framing 129:Structural Framing 15:331640
Structural Framing 130:Structural Framing 15:331652
Structural Framing 131:Structural Framing 15:331664
Structural Framing 132:Structural Framing 15:331676
Structural Framing 133:Structural Framing 15:331688
Structural Framing 134:Structural Framing 15:331700
Structural Framing 135:Structural Framing 15:331712
Structural Framing 136:Structural Framing 15:331724
Structural Framing 137:Structural Framing 15:331736
Structural Framing 138:Structural Framing 15:331748
Structural Framing 139:Structural Framing 15:331760
Structural Framing 140:Structural Framing 15:331772
Structural Framing 141:Structural Framing 15:331784
Structural Framing 142:Structural Framing 15:331796
Structural Framing 143:Structural Framing 15:331808
Structural Framing 144:Structural Framing 15:331820
Structural Framing 145:Structural Framing 15:331832
Structural Framing 146:Structural Framing 15:331844
Structural Framing 147:Structural Framing 15:331856
Structural Framing 148:Structural Framing 15:331868
Structural Framing 149:Structural Framing 15:331880
Structural Framing 150:Structural Framing 15:331891
Structural Framing 151:Structural Framing 15:331903
Structural Framing 152:Structural Framing 15:331915
Structural Framing 153:Structural Framing 15:331927
Structural Framing 154:Structural Framing 15:331939

# IfcBuildingElementProxy: Structural Framing 295, Structural Framing 295:Structural Framing 295:332342
In: Level 1
Type - Material: Wood - Generic - Wood For Showcase
Type - Pset_BuildingElementProxyCommon - Reference: Structural Framing 295
Type - Pset_ProductRequirements - Category: Structural Framing
Type - Pset_QuantityTakeOff - Reference: Structural Framing 295
Pset_BuildingElementProxyCommon - sets with these values: 2

# IfcBuildingElementProxy: Structural Framing 296 (26)
In: Level 1
Type - Material: Wood - Generic - Wood For Showcase
Type - Pset_BuildingElementProxyCommon - Reference: Structural Framing 296
Type - Pset_ProductRequirements - Category: Structural Framing
Type - Pset_QuantityTakeOff - Reference: Structural Framing 296
Pset_BuildingElementProxyCommon - sets with these values: 2
Name
Structural Framing 296:Structural Framing 296:349640
Structural Framing 297:Structural Framing 296:349778
Structural Framing 298:Structural Framing 296:349808
Structural Framing 299:Structural Framing 296:349838
Structural Framing 300:Structural Framing 296:349850
Structural Framing 301:Structural Framing 296:349868
Structural Framing 302:Structural Framing 296:349880
Structural Framing 303:Structural Framing 296:349898
Structural Framing 304:Structural Framing 296:349910
Structural Framing 305:Structural Framing 296:349928
Structural Framing 306:Structural Framing 296:349940
Structural Framing 307:Structural Framing 296:349958
Structural Framing 308:Structural Framing 296:349970
Structural Framing 309:Structural Framing 296:349988
Structural Framing 310:Structural Framing 296:350000
Structural Framing 311:Structural Framing 296:350018
Structural Framing 312:Structural Framing 296:350030
Structural Framing 313:Structural Framing 296:350048
Structural Framing 314:Structural Framing 296:350060
Structural Framing 315:Structural Framing 296:350078
Structural Framing 316:Structural Framing 296:350090
Structural Framing 317:Structural Framing 296:350108
Structural Framing 318:Structural Framing 296:350120
Structural Framing 319:Structural Framing 296:350138
Structural Framing 320:Structural Framing 296:350150
Structural Framing 322:Structural Framing 296:350180

# IfcBuildingElementProxy: Structural Framing 321, Structural Framing 321:Structural Framing 321:370704
In: Level 1
Type - Material: Steel - Generic - Black Steel
Type - Pset_BuildingElementProxyCommon - Reference: Structural Framing 321
Type - Pset_ProductRequirements - Category: Structural Framing
Type - Pset_QuantityTakeOff - Reference: Structural Framing 321
Pset_BuildingElementProxyCommon - sets with these values: 2

# IfcBuildingElementProxy: Structural Framing 323 (2)
In: Level 1
Type - Material: Steel - Generic - Black Steel
Type - Pset_BuildingElementProxyCommon - Reference: Structural Framing 323
Type - Pset_ProductRequirements - Category: Structural Framing
Type - Pset_QuantityTakeOff - Reference: Structural Framing 323
Pset_BuildingElementProxyCommon - sets with these values: 2
Name
Structural Framing 323:Structural Framing 323:371633
Structural Framing 324:Structural Framing 323:371772

# IfcDistributionPort (136)
Description: Flow; FlowDirection: SOURCEANDSINK
Name
Port_354499
Port_355628
Port_355733
Port_355931
Port_355994
Port_356179
Port_368948
Port_376161
Port_376228
Port_381722
Port_381744
Port_381754
Port_395934
Port_397362
Port_397667
Port_487199
Port_488894
Port_489124
Port_495414
Port_495438
Port_495455
Port_495472
Port_495486
Port_495503
Port_495519
Port_495633
Port_495638
Port_495652
Port_495654
Port_495668
Port_495670
Port_495682
Port_495684
Port_495698
Port_495762
Port_495786
Port_495788
Port_498469
Port_498470
Port_508846
Port_508851
Port_508880
Port_508882
Port_509027
Port_509031
Port_509033
Port_509039
Port_517179
Port_517181
Port_517182
Port_517183
Port_517184
Port_517186
Port_517205
Port_517207
Port_517208
Port_517209
Port_517210
Port_517212
Port_517229
Port_517231
Port_517272
Port_517273
Port_517288
Port_517289
Port_517300
Port_517301
Port_517800
Port_517880
Port_518140
Port_518201
Port_518335
Port_518360
Port_518440
Port_518466
Port_518521
Port_524886
Port_524887
Port_524889
Port_525041
Port_525061
Port_525062
Port_525064
Port_525066
Port_525247
Port_525248
Port_525249
Port_525250
Port_525251
Port_525252
Port_525254
Port_525255
Port_525279
Port_525280
Port_525281
Port_525282
Port_525283
Port_525284
Port_525286
Port_525287
Port_525311
Port_525312
Port_525313
Port_525314
Port_525315
Port_525316
Port_525318
Port_525319
Port_525340
Port_525341
Port_525342
Port_525343
Port_525344
Port_525345
Port_525347
Port_525348
Port_525372
Port_525373
Port_525374
Port_525375
Port_525376
Port_525377
Port_525379
Port_525380
Port_525405
Port_525406
Port_525407
Port_525408
Port_525409
Port_525410
Port_525412
Port_525413
Port_525438
Port_525439
Port_525440
Port_525441

# IfcElementAssembly: Structural Framing Assembly:Roof Construction Assembly, Structural Framing Assembly:Roof Construction Assembly:354090
In: Level 1
PredefinedType: USERDEFINED
Pset_ProductRequirements - Category: Assemblies
Pset_QuantityTakeOff - Reference: Roof Construction Assembly

# IfcRoof: Basic Roof:Generic Roof - 300mm, Basic Roof:Generic Roof - 300mm:403250
In: Level 1
Pset_ElementShading - Roughness: 914.4 mm
Pset_ProductRequirements - Category: Roofs
Pset_QuantityTakeOff - Reference: Generic Roof - 300mm
Pset_RoofCommon - IsExternal: yes; Reference: Generic Roof - 300mm; ProjectedArea: 23.447 m2; TotalArea: 27.0742 m2

# IfcSlab: Basic Roof:Generic Roof - 300mm, Basic Roof:Generic Roof - 300mm:403250
In: Level 1
PredefinedType: ROOF; Material: <Unnamed> 300 mm
Pset_ElementShading - Roughness: 914.4 mm
Pset_ProductRequirements - Category: Roofs
Pset_QuantityTakeOff - Reference: Generic Roof - 300mm; sets with these values: 2
Pset_SlabCommon - IsExternal: yes; Reference: Generic Roof - 300mm; PitchAngle: 33.0797 deg

# IfcWallStandardCase: Basic Wall:Exterior - Brick on Mtl. Stud, Basic Wall:Exterior - Brick on Mtl. Stud:396127
In: Level 1
Type - PredefinedType: STANDARD; Material: <Unnamed> 90 mm, <Unnamed> 76 mm, <Unnamed> 19 mm, <Unnamed> 152 mm, <Unnamed> 13 mm
Type - Pset_ElementShading - Roughness: 914.4 mm
Type - Pset_ProductRequirements - Category: Walls
Type - Pset_QuantityTakeOff - Reference: Exterior - Brick on Mtl. Stud
Type - Pset_ReinforcementBarPitchOfWall - Reference: Exterior - Brick on Mtl. Stud
Type - Pset_WallCommon - Reference: Exterior - Brick on Mtl. Stud; IsExternal: no
Pset_QuantityTakeOff - sets with these values: 2
Pset_WallCommon - IsExternal: yes; ExtendToStructure: no; LoadBearing: no
